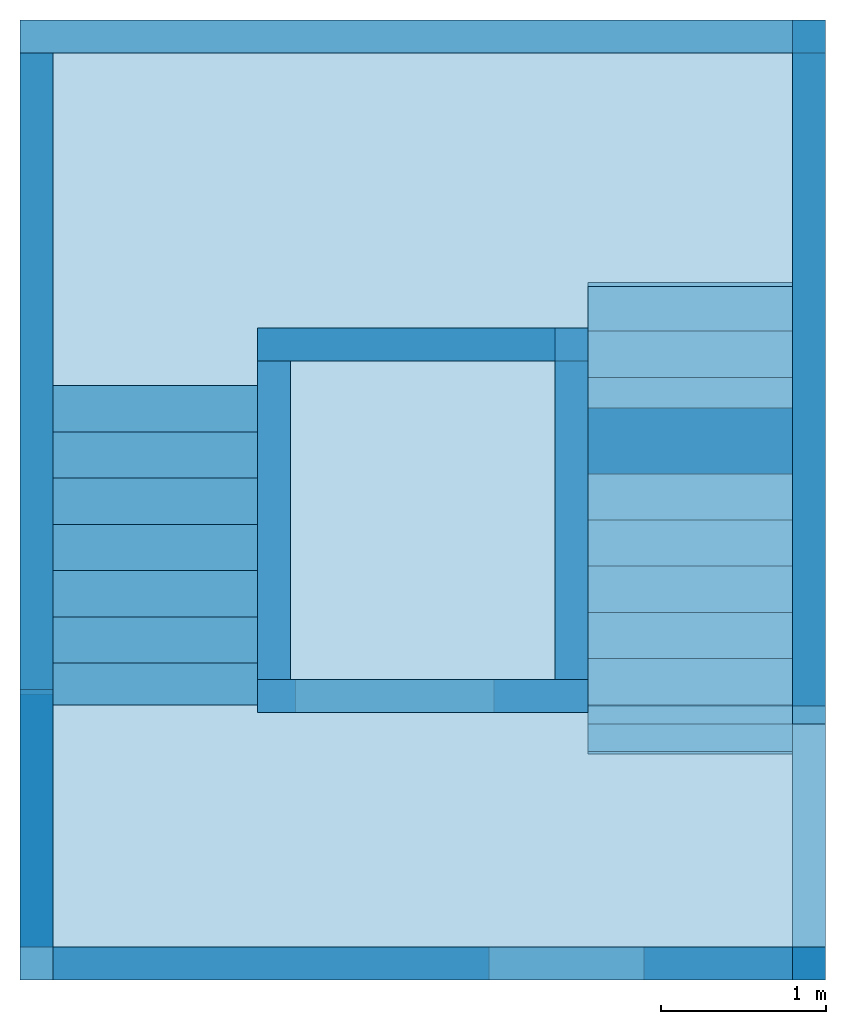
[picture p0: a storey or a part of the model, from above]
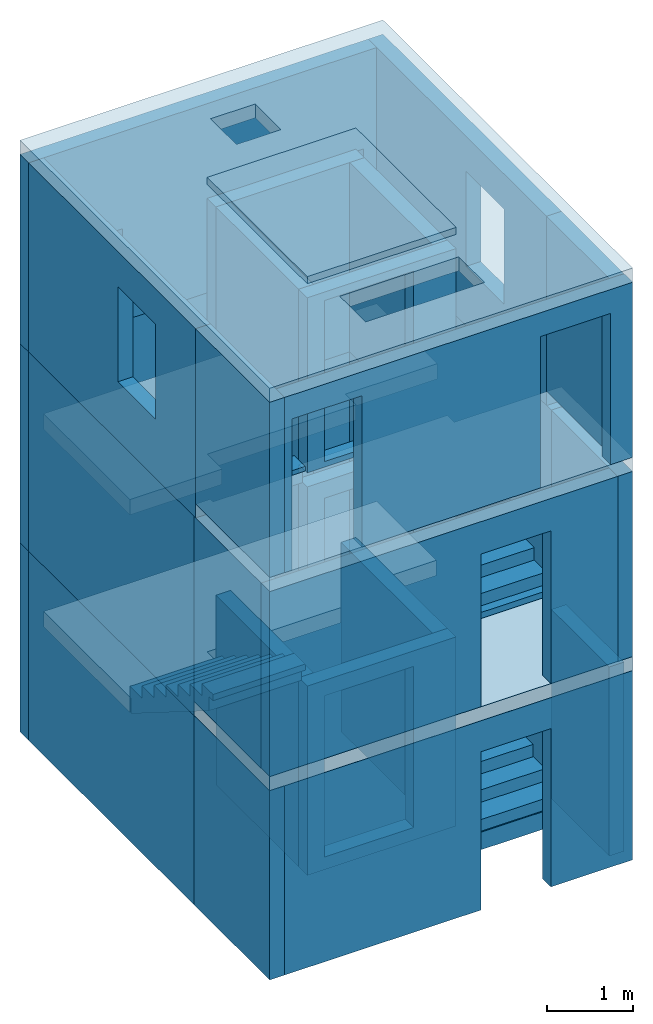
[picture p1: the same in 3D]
Properties of the parts of a building model (IFC2X3)

# File
Description: no view
File name: F.ifc
Time: 2026-08-27T15:50:17
Author: Besar Asani
Organization: No Organization
Written by: ODA SDAI 25.4
Authorization: b.asani

# IfcProject, 00'000 - Besar Asani
AllplanAttributes - Bauherr: Bauherr Name; Architekt: Architekt Name; Bauort: PLZ und Ort; Bauunternehmer Straße: Bauunternehmer Strasse; Bauunternehmer Plz/Ort: Bauunternehmer PLZ Ort; Bauherr Straße: Bauherr Strasse; Bauherr Plz/Ort: Bauherr PLZ Ort; Architekt Straße: Architekt Strasse; Architekt Plz/Ort: Architekt PLZ Ort; Projektbeschreibung: Projektbeschreibung; Bauunternehmer: Bauunternehmer Name

# IfcSite, Überbauung
RefLatitude: 48, 8, 10, 320000; RefLongitude: 11, 41, 19, 320000

# IfcBuildingStorey, Fundation & Aushub
In: F
Elevation: 0 m

# IfcOpeningElement: Opening (16)
In: Fundation & Aushub
AllplanAttributes - Object Layer Attributes #1, Status: Neubau; Object Layer Attributes #1, Versatz_oben: 0; Object Layer Attributes #1, Gewerk: Betonarbeiten; Object Layer Attributes #1, Versatz_unten: 0; Object Layer Attributes #1, Abrechnungsart: m³
Name | Object Layer Attributes #1, Türanschlag | Object Layer Attributes #1, Objektname = Object Layer Attributes #1, Bezeichnung | Object Layer Attributes #1, Allright_Bauteil_ID
Türöffnung | DIN L | Türöffnung | 7509Fen0000000011
Türöffnung | DIN L | Türöffnung | 7509Fen0000000026
Türöffnung | DIN L | Türöffnung | 7509Fen0000000023
Türöffnung | DIN L | Türöffnung | 7509Fen0000000038
Türöffnung | DIN L | Türöffnung | 7509Fen0000000044
Türöffnung | DIN L | Türöffnung | 7509Fen0000000054
Türöffnung | DIN L | Türöffnung | 7509Fen0000000063
Türöffnung | DIN L | Türöffnung | 7509Fen0000000060
Türöffnung | DIN L | Türöffnung | 7509Fen0000000078
Fensteröffnung |  | Fensteröffnung | 7509Fen0000000103
Fensteröffnung |  | Fensteröffnung | 7509Fen0000000100
Türöffnung | DIN L | Türöffnung | 7509Fen0000000118
Türöffnung | DIN L | Türöffnung | 7509Fen0000000115
Türöffnung | DIN L | Türöffnung | 7509Fen0000000127
Fensteröffnung |  | Fensteröffnung | 7509Fen0000000139
Fensteröffnung |  | Fensteröffnung | 7509Fen0000000145

# IfcSlab (6)
In: Fundation & Aushub
PredefinedType: FLOOR; Material: Béton
AllplanAttributes - Status: Neubau; Gewerk: Betonarbeiten; Material: Béton; Traduction matériau: Béton; Abrechnungsart: m³; Objektname: Decke
Pset_SlabCommon - LoadBearing: yes
Name | 2D interaktion | Allright_Bauteil_ID
 | yes | 7509De 0000000151
 | yes | 7509De 0000000149
 |  | 7509De 0000000050
 |  | 7509De 0000000094
 | yes | 7509De 0000000096
 | yes | 7509De 0000000048

# IfcWall (4)
In: Fundation & Aushub
Material: Béton
AllplanAttributes - Einheit: m³; Objektname: Wand; Attributset-Objekt: Wall; Abrechnungsart: m³; Object Layer Attributes #1, Status: Neubau; Object Layer Attributes #1, Gewerk: Betonarbeiten; Object Layer Attributes #1, Material: Béton; Object Layer Attributes #1, Material Architektur: Aussenwand Stahlbeton; Object Layer Attributes #1, Tragendes Bauteil: yes; Object Layer Attributes #1, Traduction matériau: Béton; Object Layer Attributes #1, Abrechnungsart: m³; Object Layer Attributes #1, Objektname: Wand
WallCommon - Status: Neubau
Name | Allright_Bauteil_ID | Object Layer Attributes #1, Allright_Bauteil_ID
 | 7509HWa0000000153 | 7509Wa 0000000154
 | 7509HWa0000000160 | 7509Wa 0000000161
 | 7509HWa0000000167 | 7509Wa 0000000168
 | 7509HWa0000000174 | 7509Wa 0000000175

# IfcWallStandardCase (30)
In: Fundation & Aushub
Material: Béton 0.2 m
AllplanAttributes - Einheit: m³; Objektname: Wand; Attributset-Objekt: Wall; Abrechnungsart: m³; Object Layer Attributes #1, Status: Neubau; Object Layer Attributes #1, Gewerk: Betonarbeiten; Object Layer Attributes #1, Material: Béton; Object Layer Attributes #1, Traduction matériau: Béton; Object Layer Attributes #1, Abrechnungsart: m³; Object Layer Attributes #1, Objektname: Wand
Pset_WallCommon - LoadBearing: yes
WallCommon - Status: Neubau
Name | Allright_Bauteil_ID | Object Layer Attributes #1, Tragendes Bauteil | Object Layer Attributes #1, 2D interaktion | Object Layer Attributes #1, Allright_Bauteil_ID
 | 7509HWa0000000002 | yes | yes | 7509Wa 0000000003
 | 7509HWa0000000005 | yes | yes | 7509Wa 0000000006
 | 7509HWa0000000008 | yes | yes | 7509Wa 0000000009
 | 7509HWa0000000014 | yes | yes | 7509Wa 0000000015
 | 7509HWa0000000017 | yes | yes | 7509Wa 0000000018
 | 7509HWa0000000020 | yes | yes | 7509Wa 0000000021
 | 7509HWa0000000029 | yes | yes | 7509Wa 0000000030
 | 7509HWa0000000032 | yes | yes | 7509Wa 0000000033
 | 7509HWa0000000035 | yes | yes | 7509Wa 0000000036
 | 7509HWa0000000041 | yes | yes | 7509Wa 0000000042
 | 7509HWa0000000051 | yes |  | 7509Wa 0000000052
 | 7509HWa0000000057 |  |  | 7509Wa 0000000058
 | 7509HWa0000000066 | yes |  | 7509Wa 0000000067
 | 7509HWa0000000069 | yes |  | 7509Wa 0000000070
 | 7509HWa0000000072 | yes |  | 7509Wa 0000000073
 | 7509HWa0000000075 | no | yes | 7509Wa 0000000076
 | 7509HWa0000000081 |  |  | 7509Wa 0000000082
 | 7509HWa0000000084 | no | yes | 7509Wa 0000000085
 | 7509HWa0000000087 |  |  | 7509Wa 0000000088
 | 7509HWa0000000090 | no | yes | 7509Wa 0000000091
 | 7509HWa0000000097 |  |  | 7509Wa 0000000098
 | 7509HWa0000000106 |  |  | 7509Wa 0000000107
 | 7509HWa0000000109 | no | yes | 7509Wa 0000000110
 | 7509HWa0000000112 | no | yes | 7509Wa 0000000113
 | 7509HWa0000000121 | no | yes | 7509Wa 0000000122
 | 7509HWa0000000124 | no | yes | 7509Wa 0000000125
 | 7509HWa0000000130 |  |  | 7509Wa 0000000131
 | 7509HWa0000000133 |  |  | 7509Wa 0000000134
 | 7509HWa0000000136 |  |  | 7509Wa 0000000137
 | 7509HWa0000000142 |  |  | 7509Wa 0000000143
